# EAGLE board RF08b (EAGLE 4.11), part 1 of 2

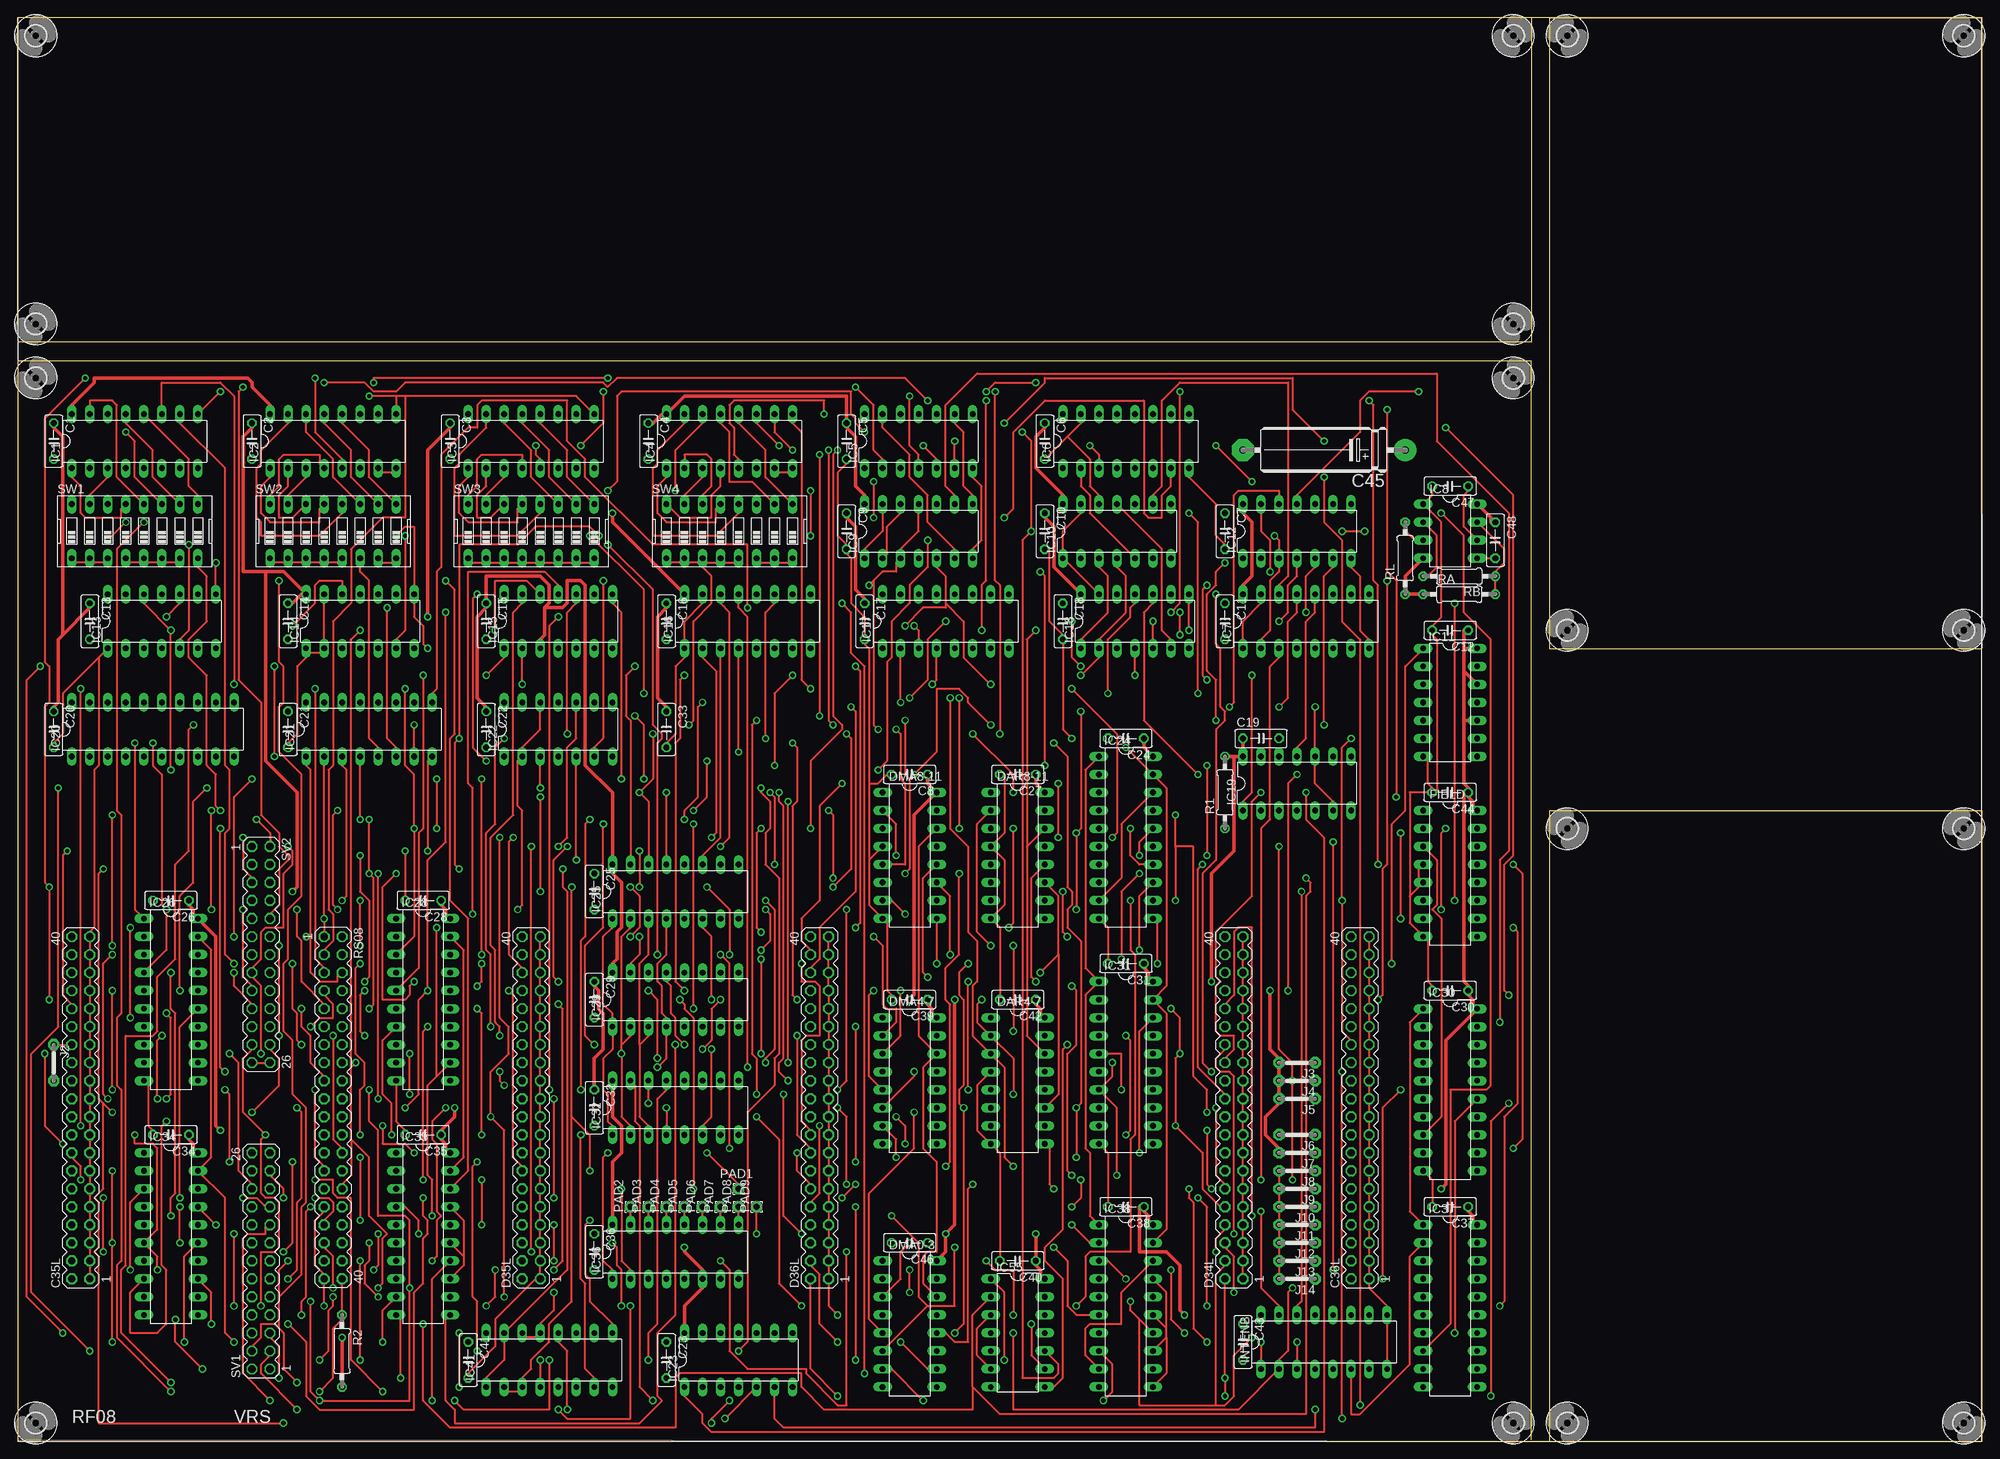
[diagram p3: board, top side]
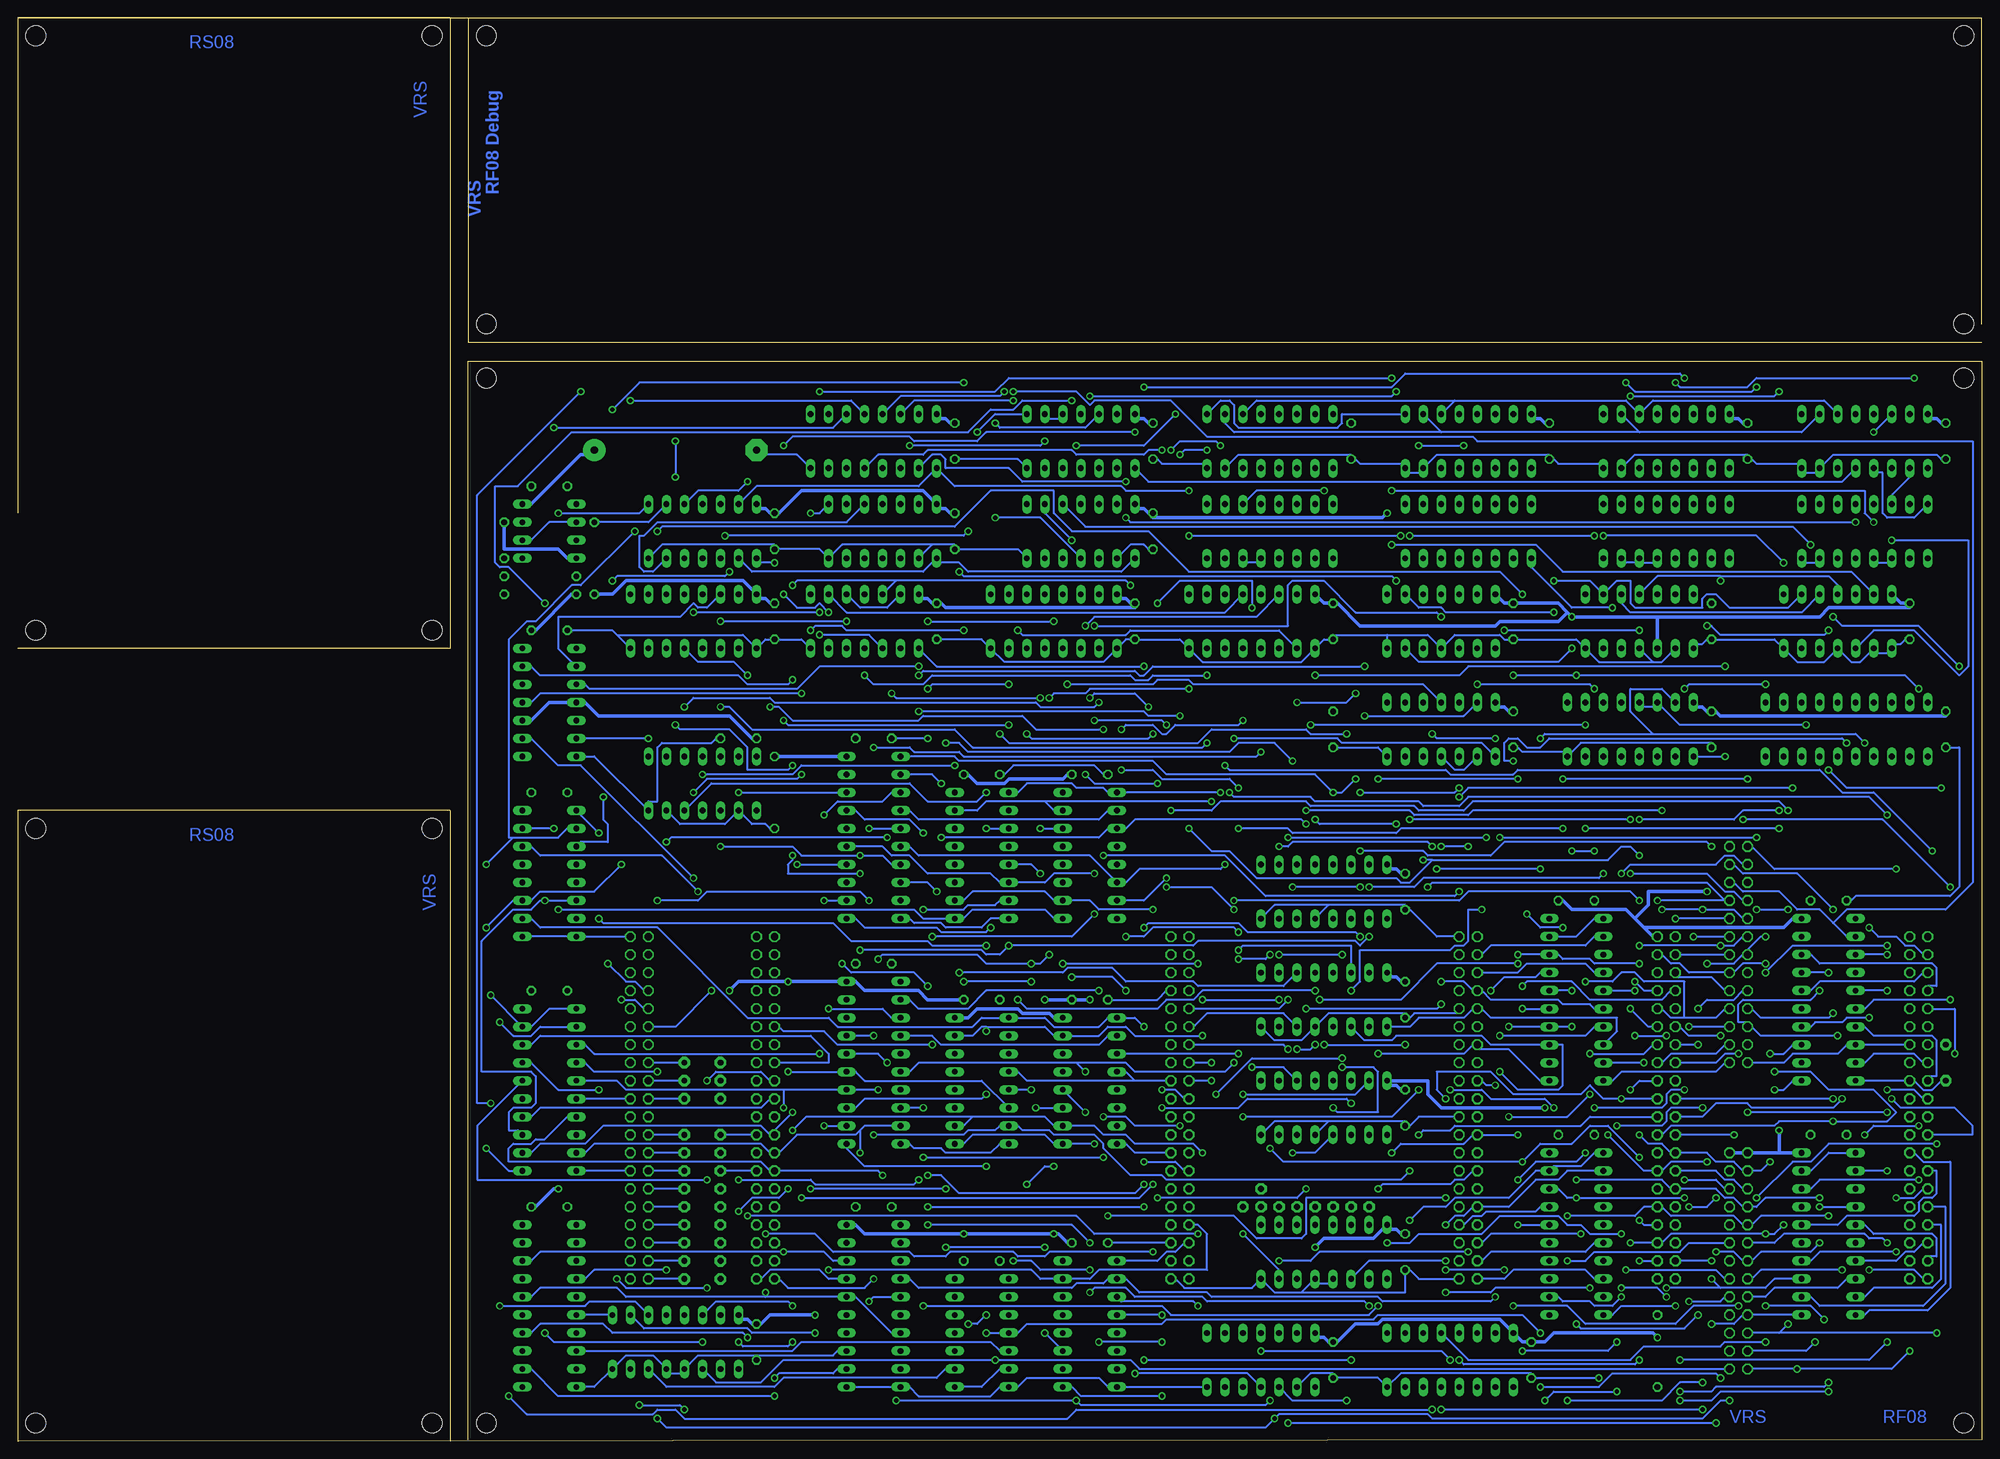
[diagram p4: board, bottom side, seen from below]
Size 276.86 x 200.67 mm. Coordinates in mm from the lower left corner, seen from the top.
Outline: 276.69,0 0.01,0.18 0.01,152.25 213.34,152.25 213.34,0.18
Outline: 215.9,0.01 215.9,88.92 276.86,88.92 276.86,0.01
Outline: 276.86,111.78 215.9,111.78 215.9,200.67 276.86,200.67
Outline: 276.86,200.67 0,200.67 0,157.49
Outline: 276.86,200.67 276.86,130.82
Outline: 0,154.95 213.36,154.95 213.36,200.67
Copper layers (1*16): Top 0.035mm / dielectric 1.5mm / Bottom 0.035mm
Design rules "olimex10mil": minimum track width 10mil, minimum drill 24mil, track to track 10mil, track to pad 10mil, pad to pad 10mil, via to via 10mil, smd to smd 10mil, copper to edge 40mil, drill to drill 10mil, minimum pad ring 10mil, minimum via ring 8mil, stop-mask expansion 0mil, vias tented up to drill 0mil, thermal gap 10mil
Net classes: 1 Power: width 0.508 mm

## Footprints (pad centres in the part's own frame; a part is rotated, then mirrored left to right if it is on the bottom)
C050-025X075 = drill 0.813 octagon: 1 -2.54,0; 2 2.54,0
MA20-2 = drill 1.016 octagon: 1 -24.13,-1.27; 2 -24.13,1.27; 3 -21.59,-1.27; 4 -21.59,1.27; 5 -19.05,-1.27; 6 -19.05,1.27; 7 -16.51,-1.27; 8 -16.51,1.27; 9 -13.97,-1.27; 10 -13.97,1.27; 11 -11.43,-1.27; 12 -11.43,1.27; 13 -8.89,-1.27; 14 -8.89,1.27; 15 -6.35,-1.27; 16 -6.35,1.27; 17 -3.81,-1.27; 18 -3.81,1.27; 19 -1.27,-1.27; 20 -1.27,1.27; 21 1.27,-1.27; 22 1.27,1.27; 23 3.81,-1.27; 24 3.81,1.27; 25 6.35,-1.27; 26 6.35,1.27; 27 8.89,-1.27; 28 8.89,1.27; 29 11.43,-1.27; 30 11.43,1.27; 31 13.97,-1.27; 32 13.97,1.27; 33 16.51,-1.27; 34 16.51,1.27; 35 19.05,-1.27; 36 19.05,1.27; 37 21.59,-1.27; 38 21.59,1.27; 39 24.13,-1.27; 40 24.13,1.27
E22-6 = drill 1.016 pad 3.15 round: + -11.43,0 | drill 1.016 pad 3.15 octagon: - 11.43,0
DIL16 = drill 0.813 long: 1 -8.89,-3.81; 2 -6.35,-3.81; 3 -3.81,-3.81; 4 -1.27,-3.81; 5 1.27,-3.81; 6 3.81,-3.81; 7 6.35,-3.81; 8 8.89,-3.81; 9 8.89,3.81; 10 6.35,3.81; 11 3.81,3.81; 12 1.27,3.81; 13 -1.27,3.81; 14 -3.81,3.81; 15 -6.35,3.81; 16 -8.89,3.81
DIL14 = drill 0.813 long: 1 -7.62,-3.81; 2 -5.08,-3.81; 3 -2.54,-3.81; 4 0,-3.81; 5 2.54,-3.81; 6 5.08,-3.81; 7 7.62,-3.81; 8 7.62,3.81; 9 5.08,3.81; 10 2.54,3.81; 11 0,3.81; 12 -2.54,3.81; 13 -5.08,3.81; 14 -7.62,3.81
DIL08 = drill 0.813 long: 1 -3.81,-3.81; 2 -1.27,-3.81; 3 1.27,-3.81; 4 3.81,-3.81; 5 3.81,3.81; 6 1.27,3.81; 7 -1.27,3.81; 8 -3.81,3.81
DIL20 = drill 0.813 long: 1 -11.43,-3.81; 2 -8.89,-3.81; 3 -6.35,-3.81; 4 -3.81,-3.81; 5 -1.27,-3.81; 6 1.27,-3.81; 7 3.81,-3.81; 8 6.35,-3.81; 9 8.89,-3.81; 10 11.43,-3.81; 11 11.43,3.81; 12 8.89,3.81; 13 6.35,3.81; 14 3.81,3.81; 15 1.27,3.81; 16 -1.27,3.81; 17 -3.81,3.81; 18 -6.35,3.81; 19 -8.89,3.81; 20 -11.43,3.81
05 = drill 0.813 pad 1.6 octagon: 1 -2.54,0; 2 2.54,0
1,6/0,8 = drill 0.813 pad 1.6 octagon: 1 0,0
0207/10 = drill 0.813 octagon: 1 -5.08,0; 2 5.08,0
MA13-2 = drill 1.016 octagon: 1 -15.24,-1.27; 2 -15.24,1.27; 3 -12.7,-1.27; 4 -12.7,1.27; 5 -10.16,-1.27; 6 -10.16,1.27; 7 -7.62,-1.27; 8 -7.62,1.27; 9 -5.08,-1.27; 10 -5.08,1.27; 11 -2.54,-1.27; 12 -2.54,1.27; 13 0,-1.27; 14 0,1.27; 15 2.54,-1.27; 16 2.54,1.27; 17 5.08,-1.27; 18 5.08,1.27; 19 7.62,-1.27; 20 7.62,1.27; 21 10.16,-1.27; 22 10.16,1.27; 23 12.7,-1.27; 24 12.7,1.27; 25 15.24,-1.27; 26 15.24,1.27
EDG-08 = drill 0.813 long: 1 -8.89,-3.81; 2 -6.35,-3.81; 3 -3.81,-3.81; 4 -1.27,-3.81; 5 1.27,-3.81; 6 3.81,-3.81; 7 6.35,-3.81; 8 8.89,-3.81; 9 8.89,3.81; 10 6.35,3.81; 11 3.81,3.81; 12 1.27,3.81; 13 -1.27,3.81; 14 -3.81,3.81; 15 -6.35,3.81; 16 -8.89,3.81
2,8 = hole 2.8: 0,0

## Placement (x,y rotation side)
C1  0.1  [C050-025X075]  5.08,140.98 270 top
C2  0.1  [C050-025X075]  33.02,140.98 270 top
C3  0.1  [C050-025X075]  60.96,140.98 270 top
C4  0.1  [C050-025X075]  88.9,140.98 270 top
C5  0.1  [C050-025X075]  116.84,140.98 270 top
C6  0.1  [C050-025X075]  144.78,140.98 270 top
C7  0.1  [C050-025X075]  170.18,128.28 270 top
C8  0.1  [C050-025X075]  125.73,94 180 top
C9  0.1  [C050-025X075]  116.84,128.28 270 top
C10  0.1  [C050-025X075]  144.78,128.28 270 top
C11  0.1  [C050-025X075]  170.18,115.58 270 top
C12  0.1  [C050-025X075]  201.93,114.31 180 top
C13  0.1  [C050-025X075]  10.16,115.58 270 top
C14  0.1  [C050-025X075]  38.1,115.58 270 top
C15  0.1  [C050-025X075]  66.04,115.58 270 top
C16  0.1  [C050-025X075]  91.44,115.58 270 top
C17  0.1  [C050-025X075]  119.38,115.58 270 top
C18  0.1  [C050-025X075]  147.32,115.58 270 top
C19  0.1  [C050-025X075]  175.26,99.08 0 top
C20  0.1  [C050-025X075]  5.08,100.34 270 top
C21  0.1  [C050-025X075]  38.1,100.34 270 top
C22  0.1  [C050-025X075]  66.04,100.34 270 top
C23  0.1  [C050-025X075]  91.44,11.45 270 top
C24  0.1  [C050-025X075]  156.21,99.08 180 top
C25  0.1  [C050-025X075]  81.28,77.48 270 top
C26  0.1  [C050-025X075]  21.59,76.22 180 top
C27  0.1  [C050-025X075]  140.97,94 180 top
C28  0.1  [C050-025X075]  57.15,76.22 180 top
C29  0.1  [C050-025X075]  81.28,62.24 270 top
C30  0.1  [C050-025X075]  201.93,63.52 180 top
C31  0.1  [C050-025X075]  156.21,67.33 180 top
C32  0.1  [C050-025X075]  81.28,47.01 270 top
C33  0.1  [C050-025X075]  91.44,100.34 270 top
C34  0.1  [C050-025X075]  21.59,43.2 180 top
C35  0.1  [C050-025X075]  57.15,43.2 180 top
C35L  [MA20-2]  8.89,47.01 90 top
C36  0.1  [C050-025X075]  81.28,26.69 270 top
C36L  [MA20-2]  189.23,47.01 90 top
C37  0.1  [C050-025X075]  201.93,33.04 180 top
C38  0.1  [C050-025X075]  156.21,33.04 180 top
C39  0.1  [C050-025X075]  125.73,62.24 180 top
C40  0.1  [C050-025X075]  140.97,25.41 180 top
C41  0.1  [C050-025X075]  63.5,11.45 270 top
C42  0.1  [C050-025X075]  140.97,62.24 180 top
C43  0.1  [C050-025X075]  172.72,13.99 270 top
C44  0.1  [C050-025X075]  201.93,91.45 180 top
C45  100uf  [E22-6]  184.15,139.71 180 top
C46  0.1  [C050-025X075]  125.73,27.96 180 top
C47  0.1  [C050-025X075]  201.93,134.63 180 top
C48  0.1  [C050-025X075]  208.28,127.02 270 top
D34L  [MA20-2]  171.45,47.01 90 top
D35L  [MA20-2]  72.39,47.01 90 top
D36L  [MA20-2]  113.03,47.01 90 top
DAR4-7  74LS193N  [DIL16]  140.97,50.81 270 top
DAR8-11  74LS193N  [DIL16]  140.97,82.56 270 top
DMA0-3  74LS193N  [DIL16]  125.73,16.53 270 top
DMA4-7  74LS193N  [DIL16]  125.73,50.81 270 top
DMA8-11  74LS193N  [DIL16]  125.73,82.56 270 top
FIELD  74LS193N  [DIL16]  201.93,80.03 270 top
IC1  74LS151N  [DIL16]  16.51,140.98 0 top
IC2  74LS151N  [DIL16]  44.45,140.98 0 top
IC3  74LS151N  [DIL16]  72.39,140.98 0 top
IC4  74LS151N  [DIL16]  100.33,140.98 0 top
IC5  74LS20N  [DIL14]  127,140.98 0 top
IC6  74LS139N  [DIL16]  156.21,140.98 0 top
IC7  74LS139N  [DIL16]  181.61,115.58 0 top
IC8  LM555N  [DIL08]  201.93,128.28 270 top
IC9  74S74N  [DIL14]  127,128.28 0 top
IC10  74S74N  [DIL14]  154.94,128.28 0 top
IC11  74S74N  [DIL14]  201.93,104.16 270 top
IC12  74LS04N  [DIL14]  180.34,128.28 0 top
IC13  74180N  [DIL14]  20.32,115.58 0 top
IC14  74180N  [DIL14]  48.26,115.58 0 top
IC15  74180N  [DIL14]  76.2,115.58 0 top
IC16  74LS139N  [DIL16]  102.87,115.58 0 top
IC17  74LS139N  [DIL16]  130.81,115.58 0 top
IC18  74LS00N  [DIL14]  157.48,115.58 0 top
IC19  7407N  [DIL14]  180.34,92.72 0 top
IC20  SPARE  [DIL20]  19.05,100.34 0 top
IC21  74LS139N  [DIL16]  49.53,100.34 0 top
IC22  7407N  [DIL14]  76.2,100.34 0 top
IC23  74S74N  [DIL14]  101.6,11.45 0 top
IC24  74S240N  [DIL20]  156.21,85.11 270 top
IC25  74S138N  [DIL16]  92.71,77.48 0 top
IC26  74S240N  [DIL20]  21.59,62.24 270 top
IC28  74LS244N  [DIL20]  57.15,62.24 270 top
IC29  74S138N  [DIL16]  92.71,62.24 0 top
IC30  74S240N  [DIL20]  201.93,49.55 270 top
IC31  74S240N  [DIL20]  156.21,53.36 270 top
IC32  74S138N  [DIL16]  92.71,47.01 0 top
IC34  74S240N  [DIL20]  21.59,29.23 270 top
IC35  74LS244N  [DIL20]  57.15,29.23 270 top
IC36  74S138N  [DIL16]  92.71,26.69 0 top
IC37  74S240N  [DIL20]  201.93,19.07 270 top
IC38  74S240N  [DIL20]  156.21,19.07 270 top
IC41  74LS139N  [DIL16]  74.93,11.45 0 top
IC55  7438N  [DIL14]  140.97,15.26 270 top
INTENB  74LS193N  [DIL16]  184.15,13.99 0 top
J2  J5MM  [05]  5.08,53.36 270 top
J3  J5MM  [05]  180.34,53.36 180 top
J4  J5MM  [05]  180.34,50.81 180 top
J5  J5MM  [05]  180.34,48.27 180 top
J6  J5MM  [05]  180.34,43.2 180 top
J7  J5MM  [05]  180.34,40.66 180 top
J8  J5MM  [05]  180.34,38.12 180 top
J9  J5MM  [05]  180.34,35.58 180 top
J10  J5MM  [05]  180.34,33.04 180 top
J11  J5MM  [05]  180.34,30.5 180 top
J12  J5MM  [05]  180.34,27.96 180 top
J13  J5MM  [05]  180.34,25.41 180 top
J14  J5MM  [05]  180.34,22.88 180 top
PAD1  [1,6/0,8]  101.6,35.58 90 top
PAD2  [1,6/0,8]  86.36,33.04 90 top
PAD3  [1,6/0,8]  88.9,33.04 90 top
PAD4  [1,6/0,8]  91.44,33.04 90 top
PAD5  [1,6/0,8]  93.98,33.04 90 top
PAD6  [1,6/0,8]  96.52,33.04 90 top
PAD7  [1,6/0,8]  99.06,33.04 90 top
PAD8  [1,6/0,8]  101.6,33.04 90 top
PAD9  [1,6/0,8]  104.14,33.04 90 top
R1  4.7K  [0207/10]  170.18,91.45 90 top
R2  4.7K  [0207/10]  45.72,12.71 270 top
RA  470K  [0207/10]  203.2,119.39 0 top
RB  1.5K  [0207/10]  203.2,121.94 180 top
RL  1K  [0207/10]  195.58,124.47 90 top
RS08  [MA20-2]  44.45,47.01 270 top
SV1  [MA13-2]  34.29,25.41 90 top
SV2  [MA13-2]  34.29,68.59 270 top
SW1  [EDG-08]  16.51,128.28 0 top
SW2  [EDG-08]  44.45,128.28 0 top
SW3  [EDG-08]  72.39,128.28 0 top
SW4  [EDG-08]  100.33,128.28 0 top
U$1  [2,8]  2.54,149.88 0 top
U$2  [2,8]  210.82,149.88 0 top
U$3  [2,8]  2.54,2.56 0 top
U$4  [2,8]  210.82,2.56 0 top
U$5  [2,8]  274.32,2.56 90 top
U$6  [2,8]  218.44,2.56 90 top
U$7  [2,8]  218.44,86.38 90 top
U$8  [2,8]  274.32,86.38 90 top
U$9  [2,8]  274.32,198.13 90 top
U$10  [2,8]  274.32,114.31 90 top
U$11  [2,8]  218.44,114.31 90 top
U$12  [2,8]  218.44,198.13 90 top
U$13  [2,8]  2.54,157.49 0 top
U$14  [2,8]  2.54,198.13 0 top
U$16  [2,8]  210.82,157.49 0 top
U$17  [2,8]  210.82,198.13 0 top
U$18  [SIERRA-PROTO]  0,0.01 0 top

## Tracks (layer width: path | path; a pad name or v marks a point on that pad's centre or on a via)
3CYC\
  Top 0.254: J2.1 C35L.28
601\  (via drill 0.61)
  Top 0.254: v89.53,5.73 87.63,7.63 87.63,44.47 87,45.1 87,50.18 IC32.15 | IC9.11 127,128.28 124.46,125.75 IC9.3 123.83,123.84 123.83,122.57 121.92,122.57 120.65,121.3 | 120.65,121.3 v120.02,120.67 | v167.64,107.33 167,107.97 167,120.03 v167.64,120.67 | v104.14,48.91 104.14,53.99 103.5,54.62 103.5,100.98 v104.14,101.61 | v121.28,100.34 120.65,100.98 120.65,121.3
  Bottom 0.254: v89.53,5.73 97.16,5.73 IC23.3 | 153.03,121.3 120.65,121.3 v120.02,120.67 | 153.03,121.3 IC18.12 | v167.64,107.33 168.28,106.7 173.99,106.7 175.26,107.97 203.2,107.97 204.47,109.23 IC11.13 | v167.64,120.67 167,121.3 153.03,121.3 | v104.14,48.91 88.27,48.91 IC32.15 | v104.14,101.61 104.78,100.98 113.67,100.98 114.94,99.71 115.57,99.71 116.84,100.98 120.65,100.98 v121.28,100.34
602\  (via drill 0.61)
  Top 0.254: v87.63,71.14 87.63,68.59 86.36,67.33 IC29.15 | v118.11,72.41 118.75,73.04 118.75,108.6 v118.11,109.23 | IC10.3 152.4,123.2 153.67,121.94 153.67,116.86 149.86,113.05 IC18.1
  Bottom 0.254: v87.63,71.14 88.27,71.77 103.5,71.77 104.78,73.04 117.47,73.04 v118.11,72.41 | v118.11,109.23 147.32,109.23 IC18.1
604\  (via drill 0.61)
  Top 0.254: v87,109.23 85.72,107.97 85.72,102.25 86.36,101.61 IC25.15 | v149.86,107.97 152.4,110.5 IC18.2 152.4,113.05 156.21,116.86 156.21,121.94 154.94,123.2 IC10.4
  Bottom 0.254: v87,109.23 116.84,109.23 118.11,107.97 118.75,107.97 119.38,108.6 149.22,108.6 v149.86,107.97
611\  (via drill 0.61)
  Top 0.254: v180.97,77.48 180.97,19.7 180.34,19.07 INTENB.14 | v115.57,47.01 116.84,45.73 v116.84,36.21 | v166.37,34.3 167.64,33.04 v167.64,19.07 | v88.9,47.64 IC32.14
  Bottom 0.254: v180.97,77.48 186.06,82.56 203.2,82.56 204.47,83.83 FIELD.14 | v88.9,47.64 89.53,48.27 103.5,48.27 104.78,47.01 v115.57,47.01 | v116.84,36.21 118.75,34.3 v166.37,34.3 | v167.64,19.07 168.28,19.7 178.44,19.7 INTENB.14
612\  (via drill 0.61)
  Top 0.254: v104.78,69.23 106.05,70.5 106.05,74.31 v105.41,74.95 | v114.94,78.12 117.47,80.66 117.47,99.08 v116.84,99.71 | v134.62,99.71 140.34,94 v140.34,91.45
  Bottom 0.254: v104.78,69.23 104.14,69.86 88.9,69.86 IC29.14 | v105.41,74.95 108.58,78.12 v114.94,78.12 | v116.84,99.71 117.47,99.08 133.99,99.08 v134.62,99.71 | v140.34,91.45 141.6,90.19 148.59,90.19 151.13,92.72 179.07,92.72 IC19.5
614\  (via drill 0.61)
  Top 0.254: v73.66,92.09 IC22.3 | IC25.14 88.9,90.19 v87.63,91.45 89.53,93.36 v89.53,99.71 | v137.79,147.97 137.79,121.3 138.43,120.67 v138.43,99.71
  Bottom 0.254: v73.66,92.09 74.3,91.45 v87.63,91.45 | v137.79,147.97 138.43,147.33 152.4,147.33 IC6.13 | v138.43,99.71 137.16,98.44 110.49,98.44 108.58,100.34 95.25,100.34 94.61,99.71 v89.53,99.71
621\  (via drill 0.61)
  Top 0.254: v88.9,11.45 88.9,15.26 90.17,16.53 90.17,48.27 91.44,49.55 IC32.13 | v118.11,33.04 v118.11,11.45 | v148.59,33.04 149.86,34.3 v149.86,36.84 | v175.26,36.84 175.26,86.38 176.53,87.64 176.53,109.23 177.8,110.5 IC7.3
  Bottom 0.254: v118.11,11.45 v88.9,11.45 | v148.59,33.04 v118.11,33.04 | v149.86,36.84 150.5,36.21 164.47,36.21 165.1,36.84 v175.26,36.84
622\  (via drill 0.61)
  Top 0.254: v93.98,55.9 92.71,57.16 92.71,59.7 92.08,60.34 92.08,64.15 91.44,64.78 IC29.13 | v96.52,55.26 97.79,56.53 97.79,60.98 v99.06,62.24 | v109.86,62.24 109.22,62.88 109.22,89.55 109.86,90.19 109.86,97.81 v109.22,98.44 | v177.8,103.52 179.07,104.79 179.07,115.58 180.34,116.86 IC7.13
  Bottom 0.254: v93.98,55.9 94.61,55.26 v96.52,55.26 | v109.86,62.24 v99.06,62.24 | v109.22,98.44 109.86,97.81 142.24,97.81 144.78,100.34 173.35,100.34 176.53,103.52 v177.8,103.52
624\  (via drill 0.61)
  Top 0.254: IC38.1 151.13,31.77 151.13,40.66 150.5,41.29 150.5,62.88 IC31.1 150.5,66.69 150.5,94.63 IC24.1 | IC25.13 v91.44,91.45 | v87,102.25 88.27,100.98 v88.27,93.36
  Bottom 0.254: IC24.1 144.78,96.53 144.15,95.9 116.84,95.9 114.94,94 93.98,94 v91.44,91.45 90.17,91.45 v88.27,93.36 | v87,102.25 73.03,102.25 IC22.13
641\  (via drill 0.61)
  Top 0.254: v102.87,52.72 102.87,116.22 101.6,117.49 IC16.13
  Bottom 0.254: v102.87,52.72 98.42,52.72 IC32.11
642\  (via drill 0.61)
  Top 0.254: v144.15,66.06 146.69,68.59 | 146.69,68.59 146.69,76.85 DAR8-11.11 | 146.69,68.59 146.69,48.91 DAR4-7.11
  Bottom 0.254: v144.15,66.06 129.54,66.06 128.91,66.69 122.56,66.69 120.65,64.78 111.12,64.78 110.49,64.15 98.42,64.15 IC29.11
644\
  Top 0.254: IC25.11 96.52,82.56 99.06,85.11 IC16.3
645\  (via drill 0.61)
  Top 0.254: IC38.19 161.93,29.86 161.93,60.34 IC31.19 161.93,64.15 161.93,92.09 IC24.19 v156.21,97.81 | v101.6,97.17 IC16.4
  Bottom 0.254: v101.6,97.17 102.23,96.53 143.51,96.53 144.15,97.17 150.5,97.17 151.13,97.81 v156.21,97.81
ACB00\  (via drill 0.61)
  Top 0.254: D34L.2 v170.18,8.91 v170.18,6.36 | v156.21,22.88 153.67,25.41 IC38.3
  Bottom 0.254: v170.18,8.91 169.54,9.54 161.93,9.54 161.29,10.18 IC38.12 | v156.21,22.88 157.48,21.61 168.28,21.61 169.54,22.88 D34L.2 | v170.18,6.36 200.66,6.36 204.47,10.18 IC37.12
ACB01\  (via drill 0.61)
  Top 0.254: 158.12,17.16 156.84,18.43 v156.84,19.7 | 158.12,17.16 IC38.14 | v173.99,14.62 171.45,12.08 171.45,6.36 170.18,5.09 168.91,5.09 | 168.91,5.09 158.12,5.09 158.12,17.16 | 168.91,5.09 168.91,23.51 170.18,24.78 D34L.4
  Bottom 0.254: v156.84,19.7 156.21,20.34 IC38.5 | v173.99,14.62 174.62,15.26 193.04,15.26 194.31,16.53 203.2,16.53 204.47,15.26 IC37.14
ACB02\  (via drill 0.61)
  Top 0.254: v171.45,20.97 171.45,26.05 170.18,27.32 D34L.6
  Bottom 0.254: IC38.7 153.67,15.26 158.75,20.34 IC38.16 171.45,20.34 | 171.45,20.34 191.13,20.34 192.41,21.61 203.2,21.61 204.47,20.34 IC37.16 | 171.45,20.34 v171.45,20.97
ACB03\  (via drill 0.61)
  Top 0.254: IC38.9 150.5,12.08 150.5,15.89 151.13,16.53 155.57,16.53 155.57,20.97 IC38.18 | v168.91,26.69 168.91,28.59 170.18,29.86 D34L.8
  Bottom 0.254: IC37.18 204.47,25.41 203.2,26.69 v168.91,26.69 163.19,26.69 161.93,25.41 IC38.18
ACB04\  (via drill 0.61)
  Top 0.254: D34L.10 169.54,33.04 167,35.58 167,40.66 v163.19,44.47 163.19,53.99 v163.83,54.62 163.83,59.7 v162.56,60.98
  Bottom 0.254: v163.19,44.47 IC31.12 | v163.83,54.62 195.58,54.62 196.85,55.9 IC30.3 | v162.56,60.98 154.94,60.98 153.67,59.7 IC31.3
ACB05\  (via drill 0.61)
  Top 0.254: v155.57,49.55 155.57,54.62 IC31.5 | v168.91,47.01 168.91,37.48 170.18,36.21 D34L.12
  Bottom 0.254: v155.57,49.55 IC31.14 168.91,49.55 | 168.91,49.55 191.13,49.55 192.41,50.81 IC30.5 | 168.91,49.55 v168.91,47.01
ACB06\  (via drill 0.61)
  Top 0.254: v154.31,53.36 154.31,51.45 IC31.7 154.94,47.01 v154.94,37.48
  Bottom 0.254: v154.31,53.36 155.57,54.62 IC31.16 | IC30.7 199.39,45.73 202.56,42.56 203.84,42.56 204.47,41.92 207.01,41.92 207.65,41.29 207.65,39.38 172.09,39.38 170.81,38.12 D34L.14 155.57,38.12 v154.94,37.48
ACB07\  (via drill 0.61)
  Top 0.254: v158.12,40.66 158.12,57.8 IC31.18
  Bottom 0.254: IC30.9 196.85,40.66 195.58,41.92 172.09,41.92 170.81,40.66 D34L.16 169.54,40.66 167,43.2 158.75,43.2 158.12,43.83 | 158.12,43.83 157.48,44.47 IC31.9 | 158.12,43.83 v158.12,40.66
ACB08\  (via drill 0.61)
  Top 0.254: 163.19,83.83 v163.19,88.28 | 163.19,83.83 v163.19,76.22 | 163.19,83.83 165.74,83.83 165.74,51.45 167.64,49.55 v167.64,46.37
  Bottom 0.254: v163.19,88.28 161.29,90.19 154.94,90.19 153.67,91.45 IC24.3 | v163.19,76.22 IC24.12 | IC30.12 204.47,40.66 203.2,41.92 196.85,41.92 194.31,44.47 172.09,44.47 170.81,43.2 D34L.18 170.18,43.83 v167.64,46.37
ACB09\  (via drill 0.61)
  Top 0.254: v156.84,86.38 156.84,82.56 158.12,81.3 IC24.14 | v167,81.3 166.37,80.66 166.37,52.72 170.18,48.91 D34L.22
  Bottom 0.254: v156.84,86.38 IC24.5 | IC30.14 204.47,45.73 203.2,47.01 172.09,47.01 170.81,48.27 D34L.22 | v167,81.3 IC24.14
ACB10\  (via drill 0.61)
  Top 0.254: v158.12,82.56 158.12,84.47 IC24.16 | v179.71,36.84 v179.71,50.81 179.71,53.36 177.8,55.26 v177.8,83.83
  Bottom 0.254: IC24.7 153.67,81.3 154.94,82.56 v158.12,82.56 166.37,82.56 167.64,83.83 v177.8,83.83 | v179.71,36.84 212.09,36.84 212.09,44.47 IC30.16 | v179.71,50.81 178.44,52.09 172.09,52.09 170.81,50.81 D34L.24
ACB11\  (via drill 0.61)
  Top 0.254: IC24.9 155.57,79.39 155.57,87.01 IC24.18 | v175.26,91.45 173.99,90.19 173.99,76.85 168.91,71.77 168.91,65.42 169.54,64.78 168.91,64.15 168.91,57.8 169.54,57.16 171.45,57.16 171.45,55.26 170.18,53.99 D34L.26
  Bottom 0.254: IC30.18 204.47,55.9 203.2,57.16 165.1,57.16 162.56,54.62 162.56,53.36 D34L.26 | v175.26,91.45 IC24.18
ACCLEAR\  (via drill 0.61)
  Top 0.254: IC22.12 73.66,100.34 71.12,97.81 IC22.2 70.48,95.9 70.48,89.55 71.12,88.92 71.12,75.58 v70.48,74.95 | v173.99,31.77 173.99,72.41 172.09,72.41 171.45,71.77 171.45,62.88 170.18,61.61 D34L.32 | v110.49,29.23 107.95,31.77 v107.95,48.91 | v90.17,53.99 90.17,62.24 v88.9,63.52
  Bottom 0.254: IC22.4 74.3,94.63 73.03,94.63 IC22.2 | v173.99,31.77 127.64,31.77 125.09,29.23 v110.49,29.23 | v107.95,48.91 102.87,53.99 v90.17,53.99 | v88.9,63.52 87.63,64.78 87.63,69.23 74.93,69.23 74.3,69.86 73.03,69.86 72.39,70.5 72.39,74.95 v70.48,74.95
BAC00  (via drill 0.61)
  Top 0.254: v115.57,6.36 111.76,10.18 D36L.2
  Bottom 0.254: v115.57,6.36 127,6.36 128.27,7.63 DMA0-3.9
BAC01  (via drill 0.61)
  Top 0.254: v124.46,13.99 128.27,10.18 DMA0-3.10 | v115.57,13.99 113.03,16.53 113.03,23.51 111.76,24.78 D36L.4
  Bottom 0.254: v115.57,13.99 v124.46,13.99
BAC02
  Bottom 0.254: DMA0-3.1 116.2,25.41 114.94,26.69 113.67,26.69 112.39,27.96 D36L.6
BAC03  (via drill 0.61)
  Top 0.254: v164.47,15.26 162.56,17.16 v162.56,24.14
  Bottom 0.254: v164.47,15.26 173.35,15.26 173.99,15.89 188.59,15.89 INTENB.10 | v162.56,24.14 133.99,24.14 132.72,22.88 DMA0-3.15 125.73,22.88 124.46,24.14 109.22,24.14 109.22,29.23 110.49,30.5 D36L.8
BAC04  (via drill 0.61)
  Top 0.254: v167.64,13.99 165.74,15.89 165.74,33.67 165.1,34.3 v165.1,35.58 | v146.05,35.58 145.41,36.21 145.41,41.29 DAR4-7.9 | v175.26,13.99 INTENB.1 | v113.03,44.47 113.03,34.94 111.76,33.67 D36L.10 | v123.83,45.73 125.09,44.47 v125.09,41.92
  Bottom 0.254: DAR4-7.9 143.51,41.92 142.24,43.2 132.08,43.2 130.81,41.92 DMA4-7.9 v125.09,41.92 | v175.26,13.99 174.62,13.35 168.28,13.35 v167.64,13.99 | v146.05,35.58 v165.1,35.58 | v113.03,44.47 119.38,44.47 120.65,45.73 v123.83,45.73
BAC05  (via drill 0.61)
  Top 0.254: v175.26,32.4 175.26,21.61 177.8,19.07 INTENB.15 | v168.28,35.58 167.64,36.21 v167.64,43.83 | v109.86,40.66 109.86,38.12 111.76,36.21 D36L.12
  Bottom 0.254: 142.24,45.73 132.08,45.73 130.81,44.47 DMA4-7.10 125.09,44.47 123.83,43.2 120.65,43.2 119.38,41.92 111.12,41.92 v109.86,40.66 | 142.24,45.73 143.51,44.47 DAR4-7.10 | v175.26,32.4 173.35,34.3 169.54,34.3 v168.28,35.58 | v167.64,43.83 165.74,45.73 142.24,45.73
BAC06  (via drill 0.61)
  Top 0.254: v118.11,58.44 v118.11,39.38
  Bottom 0.254: FIELD.10 204.47,73.67 203.2,72.41 186.69,72.41 173.99,59.7 162.56,59.7 161.29,58.44 142.24,58.44 140.97,59.7 DAR4-7.1 132.08,59.7 130.81,58.44 124.46,58.44 123.19,59.7 DMA4-7.1 119.38,59.7 v118.11,58.44 | v118.11,39.38 113.67,39.38 112.39,38.12 D36L.14
BAC07  (via drill 0.61)
  Top 0.254: v194.94,73.67 v194.94,85.74 | v140.34,69.86 v140.34,57.8 | v109.86,57.16 109.86,43.2 111.76,41.29 D36L.16
  Bottom 0.254: 140.34,58.44 140.97,58.44 142.24,57.16 DAR4-7.15 | 140.34,58.44 132.08,58.44 130.81,57.16 DMA4-7.15 124.46,57.16 123.19,58.44 120.65,58.44 119.38,57.16 v109.86,57.16 | v194.94,73.67 194.31,73.04 161.93,73.04 159.38,70.5 148.59,70.5 147.96,69.86 v140.34,69.86 | v140.34,57.8 140.34,58.44 | v194.94,85.74 FIELD.1
BAC08  (via drill 0.61)
  Top 0.254: v201.29,86.38 200.66,85.74 v200.66,74.95 | v110.49,67.33 110.49,64.78 112.39,64.78 113.03,64.15 113.03,57.16 111.12,57.16 110.49,56.53 110.49,45.1 111.76,43.83 D36L.18 | DMA8-11.9 v129.54,67.33
  Bottom 0.254: DMA8-11.9 130.81,73.67 132.08,74.95 142.24,74.95 143.51,73.67 DAR8-11.9 149.22,73.67 150.5,74.95 v200.66,74.95 | v201.29,86.38 FIELD.15 | v129.54,67.33 v110.49,67.33
BAC09  (via drill 0.61)
  Top 0.254: v115.57,49.55 116.84,50.81 v116.84,74.95
  Bottom 0.254: DAR8-11.10 143.51,76.22 142.24,77.48 132.08,77.48 130.81,76.22 DMA8-11.10 125.73,76.22 124.46,74.95 v116.84,74.95 | v115.57,49.55 113.67,49.55 112.39,48.27 D36L.22
BAC10  (via drill 0.61)
  Top 0.254: v108.58,50.81 107.31,52.09 107.31,53.36 107.95,53.99 107.95,89.55 107.31,90.19 v107.31,91.45
  Bottom 0.254: DAR8-11.1 135.89,91.45 134.62,92.72 128.27,92.72 127.64,92.09 123.83,92.09 123.19,91.45 DMA8-11.1 v107.31,91.45 | v108.58,50.81 D36L.24
BAC11  (via drill 0.61)
  Top 0.254: v108.58,53.36 v108.58,90.19
  Bottom 0.254: 132.08,90.19 130.81,88.92 DMA8-11.15 | 132.08,90.19 140.34,90.19 141.6,88.92 DAR8-11.15 | v108.58,90.19 132.08,90.19 | v108.58,53.36 D36L.26
BADDAC\  (via drill 0.61)
  Top 0.254: v193.68,67.33 193.68,87.01 195.58,88.92 195.58,109.23 IC11.1
  Bottom 0.254: v193.68,67.33 191.13,64.78 189.87,64.78 188.59,63.52 C36L.34
BBREAK  (via drill 0.61)
  Top 0.254: v123.83,100.34 124.46,99.71 124.46,93.36 125.09,92.72 125.09,81.3 DMA8-11.5 | v170.81,103.52 171.45,104.16 171.45,133.36 172.09,134 177.8,134 IC12.12
  Bottom 0.254: v123.83,100.34 133.35,100.34 135.25,102.25 149.22,102.25 149.86,101.61 167.64,101.61 169.54,103.52 v170.81,103.52
BBREAK\  (via drill 0.61)
  Top 0.254: v191.77,62.24 192.41,62.88 192.41,80.66 193.04,81.3 v193.04,121.3 | v176.53,122.57 176.53,127.02 175.26,128.28 IC12.13 | IC41.1 66.04,8.91 68.58,11.45 IC41.15 77.47,24.14 77.47,77.48 76.83,78.12 v76.83,80.66 | v16.51,98.44 16.51,74.95 IC26.1 | v62.23,80.66 61.59,81.3 61.59,98.44 v62.23,99.08 62.23,126.38 70.48,126.38 73.03,128.92 80.64,128.92 v81.92,127.65 | v111.76,134 v111.76,127.65
  Bottom 0.254: IC12.13 172.72,134.63 149.86,134.63 IC6.1 144.78,134.63 121.28,134.63 120.65,134 v111.76,134 | v191.77,62.24 189.87,62.24 188.59,60.98 C36L.32 | v193.04,121.3 192.41,121.94 177.16,121.94 v176.53,122.57 | v16.51,98.44 17.78,99.71 46.35,99.71 | 46.35,99.71 49.53,102.89 49.53,106.06 45.09,106.06 IC21.15 | v62.23,80.66 v76.83,80.66 | v62.23,99.08 61.59,99.71 46.35,99.71 | v111.76,127.65 v81.92,127.65
BINIT  (via drill 0.61)
  Top 0.254: v170.18,123.84 168.91,122.57 168.91,120.67 167.64,119.39 167.64,108.6 168.91,107.33 v168.91,101.61 | v137.16,100.98 133.99,104.16 133.99,104.79 132.72,106.06 129.54,106.06 129.54,97.17 v126.36,94 | v116.2,92.72 113.03,89.55 113.03,76.22 110.49,73.67 110.49,70.5 111.76,69.23 D36L.38
  Bottom 0.254: v170.18,123.84 172.09,123.84 IC12.1 | v168.91,101.61 168.28,100.98 v137.16,100.98 | v126.36,94 125.09,92.72 v116.2,92.72
BINIT\  (via drill 0.61)
  Top 0.254: IC9.1 119.38,125.75 121.92,128.28 IC9.13 | IC18.13 IC10.1 147.32,128.28 149.86,130.82 IC10.13 | v181.61,91.45 181.61,87.64 184.15,85.11 184.15,1.28 97.79,1.28 96.52,2.56 96.52,3.83 93.98,6.36 IC23.1 | v166.37,94 158.75,101.61 158.75,116.86 160.02,118.12 IC18.10
  Bottom 0.254: IC12.2 173.35,122.57 149.22,122.57 IC10.1 146.69,123.84 144.15,123.84 142.88,122.57 121.28,122.57 IC9.1 | v181.61,91.45 179.71,93.36 167,93.36 v166.37,94 | IC18.13 154.31,117.49 158.12,117.49 IC18.10
BIOP1  (via drill 0.61)
  Top 0.254: v97.79,55.26 97.79,45.73 96.52,44.47 IC32.6
  Bottom 0.254: v97.79,55.26 98.42,55.9 D36L.28
BIOP2
  Bottom 0.254: IC29.6 98.42,60.34 109.22,60.34 111.12,58.44 D36L.30
BIOP4  (via drill 0.61)
  Top 0.254: v97.79,62.24 97.79,71.14 96.52,72.41 IC25.6
  Bottom 0.254: v97.79,62.24 99.06,60.98 D36L.32
BMB00
  Bottom 0.254: IC35.8 54.61,22.88 55.88,24.14 66.04,24.14 67.31,22.88 D35L.2
BMB01
  Bottom 0.254: IC35.6 54.61,27.96 55.88,26.69 69.22,26.69 70.48,25.41 D35L.4
BMB02  (via drill 0.61)
  Top 0.254: v56.52,29.23 56.52,31.13 54.61,33.04 IC35.4
  Bottom 0.254: v56.52,29.23 69.22,29.23 70.48,27.96 D35L.6
BMB03  (via drill 0.61)
  Top 0.254: v75.56,30.5 v75.56,25.41
  Bottom 0.254: IC35.2 58.42,38.12 59.69,36.84 62.87,36.84 66.67,33.04 D35L.10 71.75,33.04 73.03,31.77 74.3,31.77 v75.56,30.5 | v75.56,25.41 86.36,25.41 IC36.3
BMB04  (via drill 0.61)
  Top 0.254: v69.22,63.52 69.85,62.88 69.85,40.02 71.12,38.75 D35L.14 | v85.09,35.58 85.09,25.41 86.36,24.14 IC36.2
  Bottom 0.254: v69.22,63.52 67.31,65.42 62.87,65.42 62.23,66.06 IC28.17 | v85.09,35.58 84.45,36.21 74.93,36.21 74.3,36.84 73.03,36.84 71.75,38.12 D35L.14
BMB05  (via drill 0.61)
  Top 0.254: v83.19,40.66 82.55,40.02 82.55,25.41 83.82,24.14 IC36.1 | v64.77,60.98 65.41,60.34 v65.41,43.2
  Bottom 0.254: v83.19,40.66 81.92,41.92 73.03,41.92 71.75,43.2 D35L.18 v65.41,43.2 | v64.77,60.98 IC28.15
BMB06  (via drill 0.61)
  Top 0.254: 87.63,55.9 87.63,45.73 88.9,44.47 IC32.3 | 87.63,55.9 88.9,57.16 IC29.3 | 87.63,55.9 87.63,67.33 88.9,68.59 IC25.3 | v68.58,50.18 67.94,50.81 v67.94,52.09
  Bottom 0.254: IC29.3 87,56.53 83.19,56.53 82.55,57.16 70.48,57.16 69.22,55.9 IC28.13 59.05,55.9 59.05,50.18 59.69,49.55 65.41,49.55 v67.94,52.09 | v68.58,50.18 69.85,50.18 70.48,50.81 D35L.24
BMB07  (via drill 0.61)
  Top 0.254: 85.09,55.9 v85.09,54.62 85.09,45.73 86.36,44.47 IC32.2 | 85.09,55.9 86.36,57.16 IC29.2 | 85.09,55.9 85.09,71.14 86.36,72.41 IC25.2
  Bottom 0.254: IC28.11 62.23,50.81 66.67,55.26 71.12,55.26 D35L.28 71.75,55.9 73.03,54.62 v85.09,54.62
BMB08
  Top 0.254: IC32.1 83.82,44.47 83.19,45.1 83.19,48.91 82.55,49.55 82.55,53.99 83.82,55.26 IC29.1 83.82,60.34 82.55,61.61 82.55,71.14 83.82,72.41 IC25.1
  Bottom 0.254: IC28.8 51.44,57.8 51.44,59.7 69.22,59.7 70.48,60.98 D35L.32 71.75,60.98 73.03,59.7 79.38,59.7 80.64,58.44 IC29.1
BMB09  (via drill 0.61)
  Top 0.254: v126.36,114.95 127,114.31 IC17.3 | v76.2,64.78 75.56,65.42 75.56,81.93 v77.47,83.83 | v99.06,83.83 100.33,85.11 100.33,116.86 99.06,118.12 IC16.14
  Bottom 0.254: IC28.6 54.61,60.98 55.24,61.61 59.05,61.61 59.69,62.24 69.22,62.24 70.48,63.52 D35L.34 71.75,63.52 73.03,64.78 v76.2,64.78 | v126.36,114.95 125.09,116.22 102.23,116.22 IC16.14 | v77.47,83.83 78.11,84.47 97.16,84.47 97.79,83.83 v99.06,83.83
BMB10  (via drill 0.61)
  Top 0.254: v97.79,85.11 98.42,85.74 98.42,108.6 96.52,110.5 IC16.2 | v69.85,85.11 69.22,84.47 69.22,68.59 71.12,66.69 D35L.36 | v136.53,146.7 136.53,121.3 135.89,120.67 v135.89,114.31
  Bottom 0.254: IC28.4 54.61,66.06 55.88,67.33 64.14,67.33 65.41,66.06 D35L.36 | v97.79,85.11 v69.85,85.11 | v136.53,146.7 150.5,146.7 IC6.14 | v135.89,114.31 135.25,113.68 120.65,113.68 120.02,114.31 99.06,114.31 IC16.2
BMB11
  Bottom 0.254: IC28.2 54.61,71.14 55.88,69.86 69.22,69.86 70.48,68.59 D35L.38
BRK_RQ\  (via drill 0.61)
  Top 0.254: v187.96,99.08 186.69,97.81 v186.69,76.22 186.69,57.8 187.96,56.53 C36L.28 | v50.16,24.14 50.8,24.78 v50.8,29.23 | v83.82,27.96 84.45,27.32 84.45,24.78 85.09,24.14 v85.09,19.07 | v149.22,19.07 150.5,20.34 150.5,26.05 151.13,26.69 156.84,26.69 156.84,42.56 157.48,43.2 157.48,68.59 156.84,69.23 v156.84,76.22
  Bottom 0.254: v187.96,99.08 IC11.6 | v50.16,24.14 37.47,24.14 36.2,22.88 SV1.11 | v50.8,29.23 55.24,29.23 56.52,30.5 58.42,30.5 59.69,31.77 67.94,31.77 70.48,29.23 79.38,29.23 80.64,27.96 v83.82,27.96 | v85.09,19.07 86.36,17.8 114.3,17.8 115.57,19.07 v149.22,19.07 | v156.84,76.22 158.12,77.48 179.71,77.48 180.97,76.22 v186.69,76.22
BTS1  (via drill 0.61)
  Top 0.254: v149.86,109.23 148.59,110.5 v148.59,115.58 | v130.81,115.58 128.27,113.05 128.27,107.33 v125.73,104.79 | v117.47,103.52 118.11,102.89 118.11,77.48 113.03,72.41 113.03,67.96 111.76,66.69 D36L.36
  Bottom 0.254: v149.86,109.23 163.83,109.23 167,106.06 196.22,106.06 196.85,106.7 IC11.3 | v148.59,115.58 v130.81,115.58 | v125.73,104.79 125.09,105.42 119.38,105.42 v117.47,103.52
BUSY
  Top 0.254: IC10.9 160.02,133.36 161.29,134.63 161.29,146.7 163.83,149.24 179.07,149.24 179.07,121.94 177.8,120.67 IC7.14
  Bottom 0.254: IC11.2 200.66,111.78 200.66,116.22 183.51,116.22 181.61,118.12 180.97,117.49 179.71,117.49 IC7.14
BWC0\  (via drill 0.61)
  Top 0.254: v109.22,107.97 106.68,105.42 v106.68,95.27 | v6.99,83.2 6.35,82.56 6.35,62.88 7.62,61.61 C35L.32 | v157.48,107.97 IC18.4 | v31.75,34.3 33.66,34.3 34.92,33.04 SV1.19 | v6.35,41.92 3.81,44.47 v3.81,54.62
  Bottom 0.254: v157.48,107.97 156.21,106.7 149.22,106.7 147.96,107.97 120.02,107.97 119.38,107.33 117.47,107.33 116.84,107.97 v109.22,107.97 | v106.68,95.27 106.05,94.63 75.56,94.63 74.93,94 66.04,94 65.41,94.63 22.86,94.63 19.68,91.45 15.24,91.45 v6.99,83.2 | v31.75,34.3 26.67,39.38 24.13,39.38 21.59,41.92 v6.35,41.92 | v3.81,54.62 3.81,60.98 C35L.32
CIE  (via drill 0.61)
  Top 0.254: v139.06,11.45 139.06,20.97 IC55.1 | v202.56,15.26 202.56,45.1 IC30.15 | v180.34,13.99 INTENB.3
  Bottom 0.254: INTENB.3 178.44,8.27 172.09,8.27 168.91,11.45 v139.06,11.45 120.02,11.45 118.75,10.18 SV1.1 | v202.56,15.26 201.29,13.99 v180.34,13.99
DA00\
  Bottom 0.254: J14.1 C36L.2
DA01\
  Bottom 0.254: J13.1 C36L.4
DA02\
  Bottom 0.254: J12.1 C36L.6
DA03\
  Bottom 0.254: J11.1 C36L.8
DA04\
  Bottom 0.254: J10.1 C36L.10
DA05\
  Bottom 0.254: J9.1 C36L.12
DA06\
  Bottom 0.254: J8.1 C36L.14
DA07\
  Bottom 0.254: J7.1 C36L.16
DA08\
  Bottom 0.254: J6.1 C36L.18
DA09\
  Bottom 0.254: J5.1 C36L.22
DA10\
  Bottom 0.254: J4.1 C36L.24
DA11\
  Bottom 0.254: J3.1 C36L.26
DAR04  (via drill 0.61)
  Top 0.254: v156.21,43.2 156.84,43.83 156.84,56.53 v156.21,57.16 | IC41.2 69.22,7 70.48,7 IC41.3 71.12,8.91 72.39,10.18 72.39,11.45 74.93,13.99 74.93,16.53 78.11,19.7 78.11,45.73 | v45.72,76.22 46.35,76.85 46.35,94.63 45.72,95.27 IC21.3 | 78.11,45.73 v78.11,78.12 | v80.64,38.12 80.64,43.2 78.11,45.73
  Bottom 0.254: v156.21,43.2 143.51,43.2 142.88,43.83 139.06,43.83 138.43,44.47 DAR4-7.7 135.89,44.47 135.25,43.83 131.44,43.83 130.81,43.2 125.09,43.2 123.83,41.92 123.83,41.29 120.02,37.48 115.57,37.48 114.94,36.84 81.92,36.84 v80.64,38.12 | v156.21,57.16 IC31.17 | 36.2,76.22 v45.72,76.22 | v78.11,78.12 77.47,78.75 38.73,78.75 36.2,76.22 | 36.2,76.22 SV2.8
DAR05  (via drill 0.61)
  Top 0.254: IC21.2 v43.18,73.67 RS08.1 | v168.28,52.09 167,53.36 167,80.03 168.91,81.93 168.91,100.34 170.18,101.61 170.18,102.89 169.54,103.52 169.54,111.78 168.91,112.41 v168.91,119.39 | v162.56,116.86 163.83,118.12 v163.83,147.97 | v83.19,149.88 50.16,149.88 v50.16,149.24 | v31.75,148.6 31.11,147.97 31.11,107.33 34.29,104.16 34.29,88.28 36.83,85.74 36.83,83.83 38.1,82.56 38.1,81.93 36.83,80.66 36.83,75.58 35.56,74.31 SV2.10
  Bottom 0.254: DAR4-7.6 140.97,50.81 157.48,50.81 158.75,52.09 IC31.15 v168.28,52.09 | SV2.10 v43.18,73.67 | v168.91,119.39 167,117.49 164.47,117.49 163.83,118.12 v162.56,116.86 | v163.83,147.97 139.06,147.97 137.16,149.88 v83.19,149.88 | v50.16,149.24 48.9,147.97 32.38,147.97 v31.75,148.6
DAR06  (via drill 0.61)
  Top 0.254: v140.34,48.91 140.34,53.99 DAR4-7.2 135.25,59.07 135.25,61.61 v135.89,62.24 | 41.27,71.14 41.27,66.06 42.55,64.78 45.09,64.78 45.09,66.06 RS08.6 | 41.27,71.14 41.27,94.63 40.64,95.27 IC21.1 | 41.27,71.14 v40.64,71.14 | v93.98,63.52 92.71,64.78 92.71,98.44 93.34,99.08 93.34,107.33 v93.98,107.97 | v36.2,96.53 v36.2,109.23
  Bottom 0.254: v140.34,48.91 140.97,48.27 157.48,48.27 158.75,47.01 IC31.13 | v40.64,71.14 SV2.12 | v135.89,62.24 134.62,60.98 116.2,60.98 114.94,62.24 111.12,62.24 109.86,63.52 v93.98,63.52 | v93.98,107.97 73.66,107.97 72.39,109.23 v36.2,109.23 | IC21.1 v36.2,96.53
DAR07  (via drill 0.61)
  Top 0.254: v140.34,38.75 139.06,40.02 139.06,52.72 DAR4-7.3 134.62,57.16 134.62,64.15 135.25,64.78 135.25,70.5 133.99,71.77 133.99,83.83 131.44,86.38 v131.44,104.79 | 53.34,147.33 v49.53,147.33 | v28.57,147.97 IC1.9 | 53.34,147.33 IC2.9 | 54.61,147.33 53.34,147.33 | 54.61,147.33 78.74,147.33 IC3.9 | 54.61,147.33 54.61,130.19 51.44,130.19 46.99,125.75 46.99,118.12 44.45,115.58 44.45,95.27 43.81,94.63 43.81,74.95 44.45,74.31 44.45,70.5 43.18,69.23 RS08.3 | v111.76,106.06 110.49,107.33 110.49,142.25 109.22,143.52 IC4.9
  Bottom 0.254: v140.34,38.75 157.48,38.75 160.02,41.29 IC31.11 | RS08.3 SV2.14 | v28.57,147.97 29.21,147.33 v49.53,147.33 | IC4.9 107.31,146.7 106.05,146.7 105.41,146.06 105.41,143.52 104.78,142.89 90.81,142.89 90.17,143.52 90.17,144.79 IC3.9 | v131.44,104.79 130.81,105.42 126.36,105.42 125.73,106.06 v111.76,106.06
DAR08  (via drill 0.61)
  Top 0.254: v149.22,74.95 v149.22,85.74 149.86,86.38 v149.86,102.89 | v30.48,67.33 29.21,68.59 29.21,85.74 29.84,86.38 29.84,94.63 29.21,95.27 29.21,137.17 22.86,143.52 IC1.10 | v113.03,139.08 v113.03,102.25 | v109.22,139.71 106.68,142.25 IC4.10
  Bottom 0.254: v149.22,74.95 143.51,74.95 142.88,75.58 139.06,75.58 138.43,76.22 DAR8-11.7 | v149.22,85.74 151.13,87.64 157.48,87.64 158.75,88.92 IC24.17 | RS08.4 45.09,68.59 43.81,67.33 42.55,67.33 41.27,66.06 SV2.16 34.92,66.06 33.66,67.33 v30.48,67.33 | 48.26,142.25 25.4,142.25 IC1.10 | 48.26,142.25 IC2.10 | 48.26,142.25 76.2,142.25 | 76.2,142.25 IC3.10 | 76.2,142.25 105.41,142.25 106.68,143.52 IC4.10 | v149.86,102.89 118.11,102.89 117.47,102.25 v113.03,102.25 | v113.03,139.08 112.39,139.71 v109.22,139.71
DAR09  (via drill 0.61)
  Top 0.254: v41.91,106.06 41.91,67.96 43.18,66.69 RS08.5 | v30.48,106.7 30.48,147.33 28.57,149.24 20.32,149.24 IC1.11 | v125.09,80.03 125.73,80.66 125.73,93.36 125.09,94 v125.09,101.61 | v114.94,100.98 114.3,101.61 v114.3,139.71 | v107.31,140.35 104.14,143.52 IC4.11
  Bottom 0.254: IC24.15 154.94,83.83 153.67,82.56 151.13,82.56 148.59,80.03 139.7,80.03 138.43,78.75 DAR8-11.6 132.08,78.75 130.81,80.03 v125.09,80.03 | SV2.18 36.2,63.52 38.1,65.42 43.18,65.42 RS08.5 | IC1.11 22.23,146.7 46.35,146.7 IC2.11 50.16,146.7 74.3,146.7 | 74.3,146.7 IC3.11 | 74.3,146.7 102.23,146.7 IC4.11 | v41.91,106.06 41.27,106.7 v30.48,106.7 | v125.09,101.61 115.57,101.61 v114.94,100.98 | v114.3,139.71 113.03,140.98 107.95,140.98 v107.31,140.35
DAR10  (via drill 0.61)
  Top 0.254: v137.16,69.86 135.25,71.77 135.25,87.01 DAR8-11.2 | v158.12,69.23 158.12,76.85 IC24.13 | v55.88,64.78 55.24,64.15 55.24,62.88 54.61,62.24 51.44,62.24 51.44,78.12 v53.34,80.03 | v86.36,78.12 87.63,76.85 87.63,72.41 v86.36,71.14
  Bottom 0.254: 41.91,59.7 43.81,59.7 45.09,60.98 RS08.10 | 41.91,59.7 37.47,59.7 36.2,60.98 SV2.20 | v158.12,69.23 140.97,69.23 140.34,68.59 138.43,68.59 v137.16,69.86 111.12,69.86 110.49,70.5 88.27,70.5 87.63,69.86 v86.36,71.14 | 41.91,59.7 41.91,64.78 47.62,64.78 48.9,66.06 50.8,66.06 52.07,64.78 v55.88,64.78 | v53.34,80.03 53.98,79.39 78.74,79.39 80.01,78.12 v86.36,78.12
DAR11  (via drill 0.61)
  Top 0.254: v41.27,58.44 42.55,59.7 44.45,59.7 44.45,61.61 43.18,62.88 RS08.7 | v139.7,72.41 140.34,73.04 v140.34,86.38 | v64.77,64.15 65.41,64.78 v65.41,67.33 | v93.34,62.24 93.98,61.61 93.98,60.98 95.25,59.7 v95.25,35.58 | v116.2,34.3 v118.11,36.21 | v148.59,37.48 147.96,38.12 147.96,54.62 149.22,55.9 149.22,63.52 v148.59,64.15 | v160.66,67.33 160.66,73.04 IC24.11
  Bottom 0.254: SV2.22 v41.27,58.44 | v139.7,72.41 140.34,71.77 146.69,71.77 147.32,72.41 157.48,72.41 158.75,73.67 IC24.11 | v140.34,86.38 DAR8-11.3 | v64.77,64.15 64.14,64.78 57.78,64.78 55.24,62.24 45.09,62.24 43.81,63.52 RS08.7 | v65.41,67.33 76.83,67.33 81.92,62.24 v93.34,62.24 | v95.25,35.58 96.52,34.3 v116.2,34.3 | v118.11,36.21 119.38,34.94 144.15,34.94 146.69,37.48 v148.59,37.48 | v148.59,64.15 150.5,66.06 159.38,66.06 v160.66,67.33
DATA00\  (via drill 0.61)
  Top 0.254: v15.88,24.14 15.88,33.67 IC34.3
  Bottom 0.254: v15.88,24.14 9.53,24.14 8.26,22.88 C35L.2
DATA01\
  Bottom 0.254: IC34.5 16.51,30.5 15.24,29.23 6.99,29.23 6.35,28.59 6.35,26.05 7.62,26.05 C35L.4
DATA02\
  Bottom 0.254: IC34.7 12.06,25.41 10.79,26.69 9.53,26.69 8.26,27.96 C35L.6
DATA03\
  Bottom 0.254: IC34.9 16.51,20.34 15.24,21.61 6.99,21.61 5.71,22.88 5.71,30.5 C35L.8
DATA04\
  Bottom 0.254: IC34.12 24.13,20.34 22.86,19.07 8.26,19.07 5.08,22.24 5.08,33.04 C35L.10
DATA05\  (via drill 0.61)
  Top 0.254: v12.06,26.69 v12.06,34.3
  Bottom 0.254: v12.06,26.69 22.86,26.69 24.13,25.41 IC34.14 | v12.06,34.3 9.53,34.3 8.26,35.58 C35L.12
DATA06\
  Bottom 0.254: IC34.16 20.32,30.5 19.05,31.77 9.53,31.77 8.89,32.4 8.89,33.67 8.26,34.3 6.99,34.3 6.35,34.94 6.35,38.12 C35L.14
DATA07\  (via drill 0.61)
  Top 0.254: v8.89,36.84 8.89,38.75 7.62,40.02 C35L.16
  Bottom 0.254: v8.89,36.84 22.86,36.84 24.13,35.58 IC34.18
DATA08\  (via drill 0.61)
  Top 0.254: v13.34,68.59 12.06,67.33 12.06,48.91 v12.7,48.27
  Bottom 0.254: v12.7,48.27 11.43,47.01 3.81,47.01 1.27,44.47 1.27,43.2 C35L.18 | v13.34,68.59 IC26.3
DATA09\  (via drill 0.61)
  Top 0.254: v13.34,49.55 v13.34,63.52
  Bottom 0.254: v13.34,49.55 9.53,49.55 8.26,48.27 C35L.22 | v13.34,63.52 IC26.5
DATA10\
  Bottom 0.254: IC26.7 16.51,58.44 15.24,57.16 6.99,57.16 6.35,56.53 6.35,51.45 7.62,51.45 C35L.24
DATA11\
  Bottom 0.254: IC26.9 16.51,53.36 15.24,54.62 9.53,54.62 8.26,53.36 C35L.26
DATA_IN  (via drill 0.61)
  Top 0.254: v82.55,121.3 82.55,99.08 81.28,97.81 IC22.6 | v144.15,122.57 144.78,121.94 v144.78,95.27 | v180.34,94 179.07,92.72 v179.07,63.52
  Bottom 0.254: v82.55,121.3 83.19,121.94 143.51,121.94 v144.15,122.57 | v144.78,95.27 166.37,95.27 167.64,94 v180.34,94 | v179.07,63.52 184.15,58.44 C36L.30
DCXA\
  Bottom 0.254: IC16.12 106.68,116.86 160.02,116.86 IC18.9
DIMA\  (via drill 0.61)
  Top 0.254: IC37.1 196.22,32.4 196.22,59.07 IC30.1 | v201.29,142.89 210.82,133.36 210.82,82.56 209.55,81.3 209.55,63.52 v210.19,62.88
  Bottom 0.254: IC30.1 201.93,60.98 204.47,58.44 IC30.19 v210.19,62.88 | v201.29,142.89 161.93,142.89 IC6.11
DIML\  (via drill 0.61)
  Top 0.254: v208.91,19.07 209.55,19.7 209.55,45.73 211.46,47.64 211.46,71.77 v210.82,72.41 | v190.5,146.7 191.13,146.06 191.13,121.3 191.77,120.67 v191.77,81.3
  Bottom 0.254: v208.91,19.07 196.85,19.07 196.22,19.7 189.87,19.7 INTENB.11 | v210.82,72.41 207.01,76.22 FIELD.11 204.47,76.22 203.2,77.48 195.58,77.48 v191.77,81.3 | v190.5,146.7 159.38,146.7 IC6.12
DIO00  (via drill 0.61)
  Top 0.254: v38.73,114.95 41.91,118.12 41.91,120.67 42.55,121.3 45.72,121.3 IC14.12 | IC13.12 17.78,118.12 v21.59,114.31 v21.59,94.63 | v50.8,20.34 48.9,22.24 48.9,24.78 49.53,25.41 v49.53,27.96 | v27.94,30.5 IC34.17 | v26.04,10.18 22.23,13.99 v22.23,17.16 | v30.48,19.07 v30.48,29.23 | v5.71,92.09 5.71,58.44 1.91,54.62 1.91,20.97 v10.16,12.71
  Bottom 0.254: v21.59,114.31 22.23,113.68 36.83,113.68 38.1,114.95 v38.73,114.95 | v50.8,20.34 52.07,19.07 54.61,19.07 55.24,19.7 59.05,19.7 59.69,20.34 IC35.12 | v49.53,27.96 RS08.36 45.09,27.96 43.81,29.23 v30.48,29.23 29.21,29.23 v27.94,30.5 | v22.23,17.16 24.13,19.07 v30.48,19.07 | SV1.2 v26.04,10.18 12.7,10.18 v10.16,12.71 | v21.59,94.63 19.05,92.09 v5.71,92.09
DIO01  (via drill 0.61)
  Top 0.254: v58.42,5.73 58.42,22.88 IC35.14 | v39.37,8.27 37.47,10.18 37.47,15.26 36.83,15.89 | 36.83,15.89 36.2,16.53 34.29,16.53 34.29,14.62 33.02,13.35 SV1.4 | v23.5,13.99 23.5,26.05 IC34.15 | v38.1,25.41 36.83,24.14 36.83,20.34 | 36.83,15.89 36.83,20.34 | v36.83,121.3 36.83,109.87 37.47,109.23 37.47,104.16 36.83,103.52 36.83,97.17 40.01,94 40.01,76.85 38.1,74.95 38.1,67.96 37.47,67.33 37.47,57.8 38.73,56.53 38.73,48.91 40.64,47.01 40.64,33.67 40.01,33.04 40.01,23.51 36.83,20.34
  Bottom 0.254: 36.83,121.94 45.72,121.94 IC14.11 | 36.83,121.94 21.59,121.94 20.32,120.67 IC13.11 | v58.42,5.73 45.09,5.73 42.55,8.27 v39.37,8.27 | v23.5,13.99 24.77,12.71 SV1.4 | v38.1,25.41 RS08.37 | v36.83,121.3 36.83,121.94
DIO02  (via drill 0.61)
  Top 0.254: v27.3,16.53 27.3,20.97 IC34.13 | v65.41,36.84 v65.41,30.5 | v55.88,40.66 54.61,41.92 51.44,41.92 v51.44,44.47 | v39.37,47.01 40.01,46.37 40.01,34.3 39.37,33.67 39.37,24.14 v38.1,22.88 | v44.45,21.61 44.45,26.05 43.18,27.32 RS08.35 | v20.95,116.22 22.86,118.12 IC13.10 | v3.17,109.23 1.27,107.33 1.27,20.34 v6.35,15.26
  Bottom 0.254: IC13.10 25.4,116.86 49.53,116.86 50.8,118.12 IC14.10 | 28.57,15.26 v27.3,16.53 | 28.57,15.26 SV1.6 | v65.41,36.84 62.87,39.38 57.15,39.38 v55.88,40.66 | v51.44,44.47 45.09,44.47 44.45,45.1 44.45,46.37 43.81,47.01 v39.37,47.01 | 36.83,21.61 v38.1,22.88 | 36.83,21.61 30.48,21.61 29.21,22.88 IC34.13 | v65.41,30.5 IC35.16 | 36.83,21.61 v44.45,21.61 | v20.95,116.22 19.68,114.95 8.89,114.95 v3.17,109.23 | v6.35,15.26 28.57,15.26
DIO03  (via drill 0.61)
  Top 0.254: v41.91,34.3 43.81,34.3 44.45,33.67 44.45,32.4 43.18,31.13 RS08.33 | v38.1,16.53 40.64,13.99 40.64,6.36 42.55,4.46 55.88,4.46 55.88,20.97 57.15,22.24 57.15,28.59 57.78,29.23 57.78,31.13 57.15,31.77 v57.15,34.3 | v60.33,121.3 61.59,120.03 61.59,99.71 60.96,99.08 60.96,76.22 63.5,73.67 63.5,38.12 IC35.18
  Bottom 0.254: IC13.9 27.3,117.49 35.56,117.49 37.47,119.39 38.73,119.39 39.37,118.76 39.37,117.49 48.9,117.49 49.53,118.12 49.53,121.3 51.44,121.3 IC14.9 55.24,121.3 v60.33,121.3 | IC34.11 SV1.8 33.66,17.8 34.92,16.53 v38.1,16.53 | v41.91,34.3 v57.15,34.3 58.42,34.3 59.69,35.58 IC35.18
DIO04  (via drill 0.61)
  Top 0.254: v20.95,45.1 20.32,44.47 20.32,24.78 20.95,24.14 20.95,16.53 19.68,15.26 15.88,15.26 15.88,20.97 IC34.8 | v54.61,106.06 54.61,95.27 55.88,94 v55.88,86.38 55.88,71.14 IC28.3 | v71.12,106.7 IC15.2 | v29.21,52.09 28.57,52.72 v28.57,86.38
  Bottom 0.254: IC34.8 19.05,22.88 20.32,21.61 29.21,21.61 30.48,20.34 SV1.10 | RS08.24 45.09,43.2 43.81,44.47 29.21,44.47 28.57,45.1 v20.95,45.1 13.34,45.1 12.06,46.37 15.24,49.55 21.59,49.55 24.13,52.09 v29.21,52.09 | v54.61,106.06 55.24,106.7 v71.12,106.7 | v28.57,86.38 v55.88,86.38
DIO05  (via drill 0.61)
  Top 0.254: v19.68,24.14 19.68,26.05 IC34.6 19.68,29.86 19.68,41.29 19.05,41.92 16.51,41.92 v16.51,43.2 | v57.15,107.97 57.15,86.38 56.52,85.74 56.52,66.69 IC28.5 | v66.04,107.97 68.58,110.5 IC15.1 | v44.45,57.16 44.45,42.56 45.72,41.29 RS08.26 | v48.9,57.16 48.26,57.8 48.26,62.88 v48.9,63.52 | v8.89,44.47 v8.89,106.06
  Bottom 0.254: v19.68,24.14 31.11,24.14 32.38,22.88 SV1.12 | v66.04,107.97 v57.15,107.97 10.79,107.97 v8.89,106.06 | v48.9,57.16 v44.45,57.16 | IC28.5 v48.9,63.52 | v16.51,43.2 15.24,44.47 v8.89,44.47
DIO06  (via drill 0.61)
  Top 0.254: v22.86,27.96 v22.86,33.04 | v52.7,43.2 52.7,47.64 51.44,48.91 51.44,56.53 IC28.7 | v67.94,57.16 67.94,58.44 67.31,59.07 67.31,69.23 66.67,69.86 66.67,85.11 69.85,88.28 69.85,116.86 71.12,118.12 IC15.13 | v37.47,26.69 38.73,27.96 v38.73,39.38
  Bottom 0.254: v22.86,27.96 24.13,26.69 31.11,26.69 32.38,25.41 SV1.14 33.66,25.41 34.92,26.69 v37.47,26.69 | v22.86,33.04 IC34.4 | v52.7,43.2 47.62,38.12 RS08.28 45.09,38.12 43.81,39.38 v38.73,39.38 | v67.94,57.16 55.88,57.16 54.61,58.44 IC28.7
DIO07  (via drill 0.61)
  Top 0.254: v13.34,38.12 v13.34,27.96 v13.34,13.99 | 46.99,52.72 v47.62,53.36 | 46.99,42.56 46.99,37.48 45.72,36.21 RS08.30 | 46.99,42.56 46.99,52.72 | v67.31,114.31 67.31,121.3 71.75,121.3 IC15.12 | v48.26,114.31 46.99,113.05 46.99,52.72 | v42.55,11.45 43.81,12.71 43.81,18.43 44.45,19.07 v44.45,20.34 | v50.8,21.61 51.44,22.24 51.44,28.59 52.07,29.23 49.53,31.77 49.53,40.02 46.99,42.56
  Bottom 0.254: v13.34,27.96 13.97,28.59 15.88,28.59 16.51,29.23 27.94,29.23 29.21,27.96 SV1.16 | v13.34,38.12 IC34.2 | v47.62,53.36 IC28.9 | v48.26,114.31 v67.31,114.31 | v13.34,13.99 15.88,11.45 v42.55,11.45 | v44.45,20.34 45.72,21.61 v50.8,21.61
DIO08  (via drill 0.61)
  Top 0.254: v21.59,66.06 21.59,60.98 22.23,60.34 22.23,34.94 21.59,34.3 v21.59,31.77 | 59.05,51.45 57.78,50.18 57.78,37.48 58.42,36.84 v58.42,31.77 | 59.05,51.45 IC28.12 | v64.14,74.31 64.14,92.09 63.5,92.72 63.5,122.57 74.3,122.57 76.2,120.67 IC15.11 | 59.05,51.45 v59.05,72.41
  Bottom 0.254: v21.59,31.77 31.11,31.77 32.38,30.5 SV1.18 33.66,30.5 34.92,31.77 43.81,31.77 45.09,33.04 RS08.32 47.62,33.04 48.9,31.77 v58.42,31.77 | v21.59,66.06 IC26.17 | v64.14,74.31 62.23,72.41 v59.05,72.41
DIO09  (via drill 0.61)
  Top 0.254: v22.86,34.3 22.86,58.44 IC26.15 | v57.78,58.44 57.15,57.8 v57.15,36.84 | v77.47,99.71 77.47,116.86 78.74,118.12 IC15.10 | v68.58,99.08 67.31,97.81 67.31,87.01 66.04,85.74 66.04,69.23 66.67,68.59 v66.67,58.44
  Bottom 0.254: v22.86,34.3 30.48,34.3 31.75,33.04 SV1.20 33.66,33.04 34.92,34.3 36.2,34.3 37.47,35.58 RS08.29 43.81,35.58 45.09,36.84 v57.15,36.84 | v57.78,58.44 IC28.14 v66.67,58.44 | v77.47,99.71 76.83,99.08 v68.58,99.08
DIO10  (via drill 0.61)
  Top 0.254: v29.84,54.62 31.11,53.36 31.11,38.12 33.02,36.21 SV1.22 | v60.33,116.86 60.33,84.47 57.78,81.93 v57.78,63.52 56.52,62.24 56.52,48.91 v54.61,47.01 | v41.91,49.55 41.91,40.02 43.18,38.75 RS08.27
  Bottom 0.254: v29.84,54.62 27.94,54.62 26.67,55.9 IC26.13 | RS08.27 37.47,38.12 36.2,36.84 34.92,36.84 33.66,35.58 SV1.22 | v60.33,116.86 75.56,116.86 76.2,117.49 79.38,117.49 IC15.9 | v57.78,63.52 IC28.16 | v41.91,49.55 43.81,49.55 44.45,48.91 44.45,47.64 45.09,47.01 v54.61,47.01
DIO11  (via drill 0.61)
  Top 0.254: v29.21,49.55 29.84,48.91 v29.84,39.38 | v48.26,67.33 47.62,66.69 47.62,54.62 48.9,53.36 48.9,50.18 48.26,49.55 v48.26,43.2 | v85.09,93.36 85.09,116.86 83.82,118.12 IC15.8 | v65.41,68.59 v65.41,93.36
  Bottom 0.254: v29.21,49.55 27.94,49.55 26.67,50.81 IC26.11 | v29.84,39.38 31.11,38.12 SV1.24 33.66,38.12 34.92,39.38 37.47,39.38 38.73,40.66 RS08.25 43.81,40.66 45.09,41.92 46.99,41.92 v48.26,43.2 | v48.26,67.33 54.61,67.33 55.24,67.96 59.05,67.96 59.69,68.59 IC28.18 v65.41,68.59 | v65.41,93.36 v85.09,93.36
DIOEVEN  (via drill 0.61)
  Top 0.254: v83.19,126.38 89.53,120.03 89.53,100.98 90.81,99.71 90.81,99.08 90.17,98.44 v90.17,68.59 | v99.06,68.59 100.33,67.33 v100.33,41.29 | v48.26,40.02 v48.26,31.13 | v51.44,13.99 51.44,18.43 IC35.9 | v64.77,12.71 64.77,19.7 64.14,20.34 64.14,38.75 v64.77,39.38
  Bottom 0.254: v83.19,126.38 62.87,126.38 59.05,122.57 18.41,122.57 IC13.13 | v99.06,68.59 v90.17,68.59 | v100.33,41.29 98.42,39.38 v64.77,39.38 62.23,41.92 57.78,41.92 55.24,44.47 52.7,44.47 v48.26,40.02 | v48.26,31.13 47.62,30.5 RS08.34 | v51.44,13.99 52.7,12.71 v64.77,12.71
DMA00  (via drill 0.61)
  Top 0.254: v127.64,5.73 123.19,10.18 DMA0-3.7 | v153.03,5.73 154.31,7 154.31,10.81 IC38.8 | v12.06,80.66 11.43,80.03 11.43,48.27 12.06,47.64 | 12.06,47.64 v13.34,46.37 | v33.02,46.37 36.83,50.18 36.83,53.99 35.56,55.26 SV2.24 | v100.33,5.73 97.79,3.19 v97.79,2.56 | v37.47,2.56 11.43,2.56 11.43,26.05 10.79,26.69 11.43,27.32 11.43,33.67 10.79,34.3 12.06,35.58 12.06,47.64
  Bottom 0.254: v153.03,5.73 v127.64,5.73 127,5.09 100.97,5.09 v100.33,5.73 | SV2.24 36.2,55.9 37.47,54.62 43.81,54.62 45.09,53.36 RS08.16 | v12.06,80.66 29.21,80.66 32.38,83.83 SV2.1 | v13.34,46.37 v33.02,46.37 | v37.47,2.56 v97.79,2.56
DMA01  (via drill 0.61)
  Top 0.254: 128.27,19.07 132.08,19.07 v132.08,27.32 | v146.05,27.32 147.96,25.41 147.96,19.07 149.22,17.8 IC38.6 | 128.27,19.07 DMA0-3.6 | v50.8,48.27 v50.8,80.03 | 128.27,19.07 127,20.34 127,27.96 v123.19,31.77 | v75.56,48.27 v75.56,34.3
  Bottom 0.254: v132.08,27.32 v146.05,27.32 | v50.8,80.03 49.53,81.3 37.47,81.3 36.2,82.56 34.92,82.56 33.66,81.3 SV2.3 | RS08.20 v50.8,48.27 53.34,48.27 55.24,50.18 56.52,48.91 66.04,48.91 69.22,52.09 76.83,52.09 76.83,49.55 v75.56,48.27 | v123.19,31.77 105.41,31.77 102.23,28.59 95.89,28.59 95.25,29.23 95.25,34.3 v75.56,34.3
DMA02  (via drill 0.61)
  Top 0.254: v55.24,48.91 v55.24,54.62 | v68.58,20.34 68.58,43.83 v66.67,45.73 66.67,52.09 69.22,54.62 69.22,58.44 67.94,59.7 v67.94,85.11 | v31.75,85.11 31.75,80.66 33.02,79.39 SV2.5
  Bottom 0.254: IC38.4 151.13,22.88 149.86,21.61 128.27,21.61 127.64,22.24 123.83,22.24 123.19,22.88 DMA0-3.2 120.65,22.88 118.75,20.97 109.22,20.97 108.58,20.34 85.09,20.34 84.45,19.7 69.22,19.7 v68.58,20.34 | v55.24,54.62 47.62,54.62 46.35,55.9 RS08.14 | v55.24,48.91 58.42,45.73 v66.67,45.73 | v67.94,85.11 v31.75,85.11
DMA03  (via drill 0.61)
  Top 0.254: v49.53,60.98 50.16,61.61 50.16,79.39 v49.53,80.03 v49.53,87.64 | v125.73,27.96 124.46,26.69 124.46,22.88 DMA0-3.3 | v148.59,30.5 151.13,27.96 IC38.2 | v80.64,87.64 80.01,87.01 80.01,71.14 79.38,70.5 v79.38,49.55 | v104.14,45.73 107.31,42.56 107.31,22.24 v110.49,19.07
  Bottom 0.254: v49.53,80.03 38.73,80.03 36.2,77.48 34.92,77.48 33.66,76.22 SV2.7 | v49.53,60.98 46.99,58.44 RS08.12 | v125.73,27.96 128.27,30.5 v148.59,30.5 | v49.53,87.64 v80.64,87.64 | v79.38,49.55 83.19,45.73 v104.14,45.73 | v110.49,19.07 111.12,19.7 121.28,19.7 DMA0-3.3
DMA04  (via drill 0.61)
  Top 0.254: v39.37,74.95 39.37,71.14 40.01,70.5 40.01,64.78 43.18,61.61 RS08.9 | v123.83,40.02 123.83,42.56 DMA4-7.7 | v149.22,40.02 v149.22,47.01 149.86,47.64 149.86,70.5 147.96,72.41 147.96,74.95 148.59,75.58 148.59,77.48 147.96,78.12 147.96,96.53 v146.05,98.44 | v45.09,74.95 44.45,75.58 44.45,88.28 v45.09,88.92 | v95.25,88.92 97.16,90.82 v97.16,95.9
